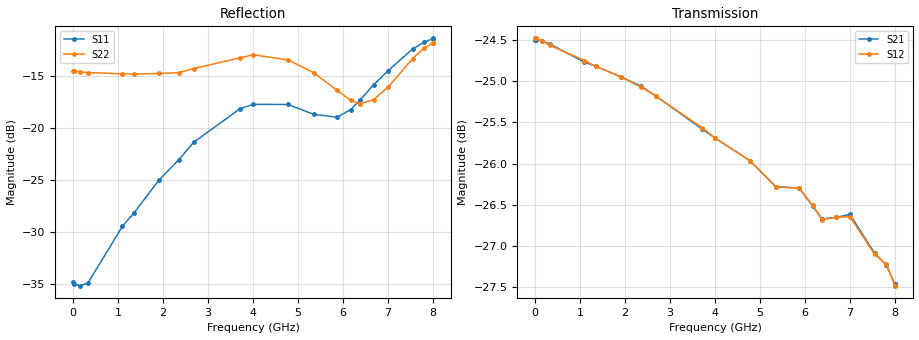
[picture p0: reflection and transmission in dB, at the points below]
! DEVICE ID: PE43712
! File Path: z:\PE43713\PE43713_CHAR_NOM_04292014\AMB\3p300\LS_ATT_23p25dB\PE43713_AMB_3p300V_3p000V_0p000V_LS_ATT_23p25dB_S2P_SN_10_A0139A.s2p
! Serial: 10
! Lot: A0139A
! Temp: 25C
! VDD: 3.300
! VSS: 0.000
! Control_Hi: 3.000
! Control_Lo: 0.000
! Attenuation Step: 23.25dB
! Port 1: RF1
! Port 2: RF2
! ThroughPath:1-2
! IDD: 0.0001474516
! ISS: -7.22e-008
#  Hz  S  RI  R  50
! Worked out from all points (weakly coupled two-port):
!   801 points, 10 MHz to 8.01 GHz, reference 50 ohm
!   highest |S21| = -24.49 dB at 30 MHz (marker M1); lowest = -27.5 dB at 8 GHz (marker M2)
!   lowest |S11| = -35.2 dB at 160 MHz (marker M3), VSWR 1.04, Z = 48.4 + j0.523 ohm
!   |S11| at or under -10 dB: start of sweep to end of sweep
!   |S22| runs from -17.7 to -11.8 dB; largest |S21 - S12| = 0.00021
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1e7  -0.018 0.000669  0.0596 -0.000275  0.0597 -0.00027  -0.1889 0.00122
3e7  -0.0176 0.00166  0.0596 -0.000726  0.0597 -0.000714  -0.1883 0.00301
1.6e8  -0.0165 0.00541  0.0594 -0.00354  0.0594 -0.00353  -0.1867 0.012
3.3e8  -0.015 0.00969  0.0588 -0.00714  0.0587 -0.00706  -0.1842 0.0219
1.1e9  -0.01 0.0321  0.0536 -0.0215  0.0537 -0.0216  -0.1699 0.0679
1.35e9  -0.00643 0.0383  0.0514 -0.0256  0.0514 -0.0256  -0.1636 0.0806
1.91e9  0.00509 0.0559  0.0453 -0.0339  0.0453 -0.0339  -0.1442 0.1138
2.35e9  0.0169 0.0683  0.0394 -0.0396  0.0394 -0.0395  -0.1257 0.136
2.68e9  0.0272 0.0809  0.0347 -0.0428  0.0347 -0.0428  -0.1112 0.1589
3.71e9  0.0448 0.1156  0.0181 -0.0494  0.0181 -0.0495  -0.0829 0.202
4.01e9  0.0472 0.1214  0.0133 -0.0502  0.0133 -0.0502  -0.0811 0.211
4.78e9  0.0542 0.1183  0.00144 -0.0503  0.00146 -0.0503  -0.065 0.2034
5.35e9  0.0686 0.0943  -0.00642 -0.0481  -0.0064 -0.0481  -0.0475 0.1791
5.87e9  0.0908 0.0671  -0.0136 -0.0465  -0.0135 -0.0465  -0.00916 0.1521
6.17e9  0.1094 0.056  -0.0182 -0.0436  -0.0181 -0.0437  0.0211 0.1346
6.38e9  0.1263 0.0521  -0.0197 -0.042  -0.0196 -0.042  0.0457 0.123
6.68e9  0.155 0.0465  -0.023 -0.0404  -0.023 -0.0404  0.0831 0.1094
7e9  0.1833 0.0458  -0.0274 -0.0378  -0.0273 -0.0377  0.118 0.1043
7.55e9  0.2356 0.0519  -0.0323 -0.0302  -0.0322 -0.0302  0.1844 0.1135
7.81e9  0.2537 0.0581  -0.0337 -0.0275  -0.0337 -0.0276  0.212 0.1217
8e9  0.2633 0.0627  -0.0341 -0.0251  -0.034 -0.0251  0.2247 0.1246
8.01e9  0.2638 0.0634  -0.0341 -0.0251  -0.034 -0.0251  0.2254 0.1247
